# Generated by FakeRAM 2.0
VERSION 5.7 ;
BUSBITCHARS "[]" ;
PROPERTYDEFINITIONS
  MACRO width INTEGER ;
  MACRO depth INTEGER ;
  MACRO banks INTEGER ;
END PROPERTYDEFINITIONS
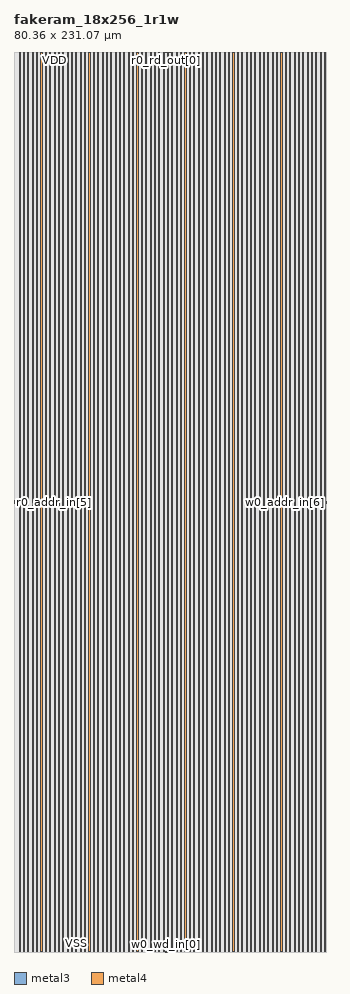
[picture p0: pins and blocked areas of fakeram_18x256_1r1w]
MACRO fakeram_18x256_1r1w
  PROPERTY width 18 ;
  PROPERTY depth 256 ;
  PROPERTY banks 1 ;
  FOREIGN fakeram_18x256_1r1w 0 0 ;
  SYMMETRY X Y R90 ;
  SIZE 80.360 BY 231.070 ;
  CLASS BLOCK ;
  PIN r0_addr_in[0]
    DIRECTION INPUT ;
    USE SIGNAL ;
    SHAPE ABUTMENT ;
    PORT
      LAYER metal3 ;
      RECT 0.000 114.800 0.070 114.870 ;
    END
  END r0_addr_in[0]
  PIN r0_addr_in[1]
    DIRECTION INPUT ;
    USE SIGNAL ;
    SHAPE ABUTMENT ;
    PORT
      LAYER metal3 ;
      RECT 0.000 114.940 0.070 115.010 ;
    END
  END r0_addr_in[1]
  PIN r0_addr_in[2]
    DIRECTION INPUT ;
    USE SIGNAL ;
    SHAPE ABUTMENT ;
    PORT
      LAYER metal3 ;
      RECT 0.000 115.080 0.070 115.150 ;
    END
  END r0_addr_in[2]
  PIN r0_addr_in[3]
    DIRECTION INPUT ;
    USE SIGNAL ;
    SHAPE ABUTMENT ;
    PORT
      LAYER metal3 ;
      RECT 0.000 115.220 0.070 115.290 ;
    END
  END r0_addr_in[3]
  PIN r0_addr_in[4]
    DIRECTION INPUT ;
    USE SIGNAL ;
    SHAPE ABUTMENT ;
    PORT
      LAYER metal3 ;
      RECT 0.000 115.360 0.070 115.430 ;
    END
  END r0_addr_in[4]
  PIN r0_addr_in[5]
    DIRECTION INPUT ;
    USE SIGNAL ;
    SHAPE ABUTMENT ;
    PORT
      LAYER metal3 ;
      RECT 0.000 115.500 0.070 115.570 ;
    END
  END r0_addr_in[5]
  PIN r0_addr_in[6]
    DIRECTION INPUT ;
    USE SIGNAL ;
    SHAPE ABUTMENT ;
    PORT
      LAYER metal3 ;
      RECT 0.000 115.640 0.070 115.710 ;
    END
  END r0_addr_in[6]
  PIN r0_addr_in[7]
    DIRECTION INPUT ;
    USE SIGNAL ;
    SHAPE ABUTMENT ;
    PORT
      LAYER metal3 ;
      RECT 0.000 115.780 0.070 115.850 ;
    END
  END r0_addr_in[7]
  PIN r0_ce_in
    DIRECTION INPUT ;
    USE SIGNAL ;
    SHAPE ABUTMENT ;
    PORT
      LAYER metal3 ;
      RECT 0.000 116.060 0.070 116.130 ;
    END
  END r0_ce_in
  PIN r0_clk
    DIRECTION INPUT ;
    USE SIGNAL ;
    SHAPE ABUTMENT ;
    PORT
      LAYER metal3 ;
      RECT 0.000 116.200 0.070 116.270 ;
    END
  END r0_clk
  PIN r0_rd_out[0]
    DIRECTION OUTPUT ;
    USE SIGNAL ;
    SHAPE ABUTMENT ;
    PORT
      LAYER metal3 ;
      RECT 38.885 231.000 38.955 231.070 ;
    END
  END r0_rd_out[0]
  PIN r0_rd_out[1]
    DIRECTION OUTPUT ;
    USE SIGNAL ;
    SHAPE ABUTMENT ;
    PORT
      LAYER metal3 ;
      RECT 39.025 231.000 39.095 231.070 ;
    END
  END r0_rd_out[1]
  PIN r0_rd_out[2]
    DIRECTION OUTPUT ;
    USE SIGNAL ;
    SHAPE ABUTMENT ;
    PORT
      LAYER metal3 ;
      RECT 39.165 231.000 39.235 231.070 ;
    END
  END r0_rd_out[2]
  PIN r0_rd_out[3]
    DIRECTION OUTPUT ;
    USE SIGNAL ;
    SHAPE ABUTMENT ;
    PORT
      LAYER metal3 ;
      RECT 39.305 231.000 39.375 231.070 ;
    END
  END r0_rd_out[3]
  PIN r0_rd_out[4]
    DIRECTION OUTPUT ;
    USE SIGNAL ;
    SHAPE ABUTMENT ;
    PORT
      LAYER metal3 ;
      RECT 39.445 231.000 39.515 231.070 ;
    END
  END r0_rd_out[4]
  PIN r0_rd_out[5]
    DIRECTION OUTPUT ;
    USE SIGNAL ;
    SHAPE ABUTMENT ;
    PORT
      LAYER metal3 ;
      RECT 39.585 231.000 39.655 231.070 ;
    END
  END r0_rd_out[5]
  PIN r0_rd_out[6]
    DIRECTION OUTPUT ;
    USE SIGNAL ;
    SHAPE ABUTMENT ;
    PORT
      LAYER metal3 ;
      RECT 39.725 231.000 39.795 231.070 ;
    END
  END r0_rd_out[6]
  PIN r0_rd_out[7]
    DIRECTION OUTPUT ;
    USE SIGNAL ;
    SHAPE ABUTMENT ;
    PORT
      LAYER metal3 ;
      RECT 39.865 231.000 39.935 231.070 ;
    END
  END r0_rd_out[7]
  PIN r0_rd_out[8]
    DIRECTION OUTPUT ;
    USE SIGNAL ;
    SHAPE ABUTMENT ;
    PORT
      LAYER metal3 ;
      RECT 40.005 231.000 40.075 231.070 ;
    END
  END r0_rd_out[8]
  PIN r0_rd_out[9]
    DIRECTION OUTPUT ;
    USE SIGNAL ;
    SHAPE ABUTMENT ;
    PORT
      LAYER metal3 ;
      RECT 40.145 231.000 40.215 231.070 ;
    END
  END r0_rd_out[9]
  PIN r0_rd_out[10]
    DIRECTION OUTPUT ;
    USE SIGNAL ;
    SHAPE ABUTMENT ;
    PORT
      LAYER metal3 ;
      RECT 40.285 231.000 40.355 231.070 ;
    END
  END r0_rd_out[10]
  PIN r0_rd_out[11]
    DIRECTION OUTPUT ;
    USE SIGNAL ;
    SHAPE ABUTMENT ;
    PORT
      LAYER metal3 ;
      RECT 40.425 231.000 40.495 231.070 ;
    END
  END r0_rd_out[11]
  PIN r0_rd_out[12]
    DIRECTION OUTPUT ;
    USE SIGNAL ;
    SHAPE ABUTMENT ;
    PORT
      LAYER metal3 ;
      RECT 40.565 231.000 40.635 231.070 ;
    END
  END r0_rd_out[12]
  PIN r0_rd_out[13]
    DIRECTION OUTPUT ;
    USE SIGNAL ;
    SHAPE ABUTMENT ;
    PORT
      LAYER metal3 ;
      RECT 40.705 231.000 40.775 231.070 ;
    END
  END r0_rd_out[13]
  PIN r0_rd_out[14]
    DIRECTION OUTPUT ;
    USE SIGNAL ;
    SHAPE ABUTMENT ;
    PORT
      LAYER metal3 ;
      RECT 40.845 231.000 40.915 231.070 ;
    END
  END r0_rd_out[14]
  PIN r0_rd_out[15]
    DIRECTION OUTPUT ;
    USE SIGNAL ;
    SHAPE ABUTMENT ;
    PORT
      LAYER metal3 ;
      RECT 40.985 231.000 41.055 231.070 ;
    END
  END r0_rd_out[15]
  PIN r0_rd_out[16]
    DIRECTION OUTPUT ;
    USE SIGNAL ;
    SHAPE ABUTMENT ;
    PORT
      LAYER metal3 ;
      RECT 41.125 231.000 41.195 231.070 ;
    END
  END r0_rd_out[16]
  PIN r0_rd_out[17]
    DIRECTION OUTPUT ;
    USE SIGNAL ;
    SHAPE ABUTMENT ;
    PORT
      LAYER metal3 ;
      RECT 41.265 231.000 41.335 231.070 ;
    END
  END r0_rd_out[17]
  PIN w0_addr_in[0]
    DIRECTION INPUT ;
    USE SIGNAL ;
    SHAPE ABUTMENT ;
    PORT
      LAYER metal3 ;
      RECT 80.290 114.660 80.360 114.730 ;
    END
  END w0_addr_in[0]
  PIN w0_addr_in[1]
    DIRECTION INPUT ;
    USE SIGNAL ;
    SHAPE ABUTMENT ;
    PORT
      LAYER metal3 ;
      RECT 80.290 114.800 80.360 114.870 ;
    END
  END w0_addr_in[1]
  PIN w0_addr_in[2]
    DIRECTION INPUT ;
    USE SIGNAL ;
    SHAPE ABUTMENT ;
    PORT
      LAYER metal3 ;
      RECT 80.290 114.940 80.360 115.010 ;
    END
  END w0_addr_in[2]
  PIN w0_addr_in[3]
    DIRECTION INPUT ;
    USE SIGNAL ;
    SHAPE ABUTMENT ;
    PORT
      LAYER metal3 ;
      RECT 80.290 115.080 80.360 115.150 ;
    END
  END w0_addr_in[3]
  PIN w0_addr_in[4]
    DIRECTION INPUT ;
    USE SIGNAL ;
    SHAPE ABUTMENT ;
    PORT
      LAYER metal3 ;
      RECT 80.290 115.220 80.360 115.290 ;
    END
  END w0_addr_in[4]
  PIN w0_addr_in[5]
    DIRECTION INPUT ;
    USE SIGNAL ;
    SHAPE ABUTMENT ;
    PORT
      LAYER metal3 ;
      RECT 80.290 115.360 80.360 115.430 ;
    END
  END w0_addr_in[5]
  PIN w0_addr_in[6]
    DIRECTION INPUT ;
    USE SIGNAL ;
    SHAPE ABUTMENT ;
    PORT
      LAYER metal3 ;
      RECT 80.290 115.500 80.360 115.570 ;
    END
  END w0_addr_in[6]
  PIN w0_addr_in[7]
    DIRECTION INPUT ;
    USE SIGNAL ;
    SHAPE ABUTMENT ;
    PORT
      LAYER metal3 ;
      RECT 80.290 115.640 80.360 115.710 ;
    END
  END w0_addr_in[7]
  PIN w0_we_in
    DIRECTION INPUT ;
    USE SIGNAL ;
    SHAPE ABUTMENT ;
    PORT
      LAYER metal3 ;
      RECT 80.290 115.920 80.360 115.990 ;
    END
  END w0_we_in
  PIN w0_ce_in
    DIRECTION INPUT ;
    USE SIGNAL ;
    SHAPE ABUTMENT ;
    PORT
      LAYER metal3 ;
      RECT 80.290 116.060 80.360 116.130 ;
    END
  END w0_ce_in
  PIN w0_clk
    DIRECTION INPUT ;
    USE SIGNAL ;
    SHAPE ABUTMENT ;
    PORT
      LAYER metal3 ;
      RECT 80.290 116.200 80.360 116.270 ;
    END
  END w0_clk
  PIN w0_wd_in[0]
    DIRECTION INPUT ;
    USE SIGNAL ;
    SHAPE ABUTMENT ;
    PORT
      LAYER metal3 ;
      RECT 38.885 0.000 38.955 0.070 ;
    END
  END w0_wd_in[0]
  PIN w0_wd_in[1]
    DIRECTION INPUT ;
    USE SIGNAL ;
    SHAPE ABUTMENT ;
    PORT
      LAYER metal3 ;
      RECT 39.025 0.000 39.095 0.070 ;
    END
  END w0_wd_in[1]
  PIN w0_wd_in[2]
    DIRECTION INPUT ;
    USE SIGNAL ;
    SHAPE ABUTMENT ;
    PORT
      LAYER metal3 ;
      RECT 39.165 0.000 39.235 0.070 ;
    END
  END w0_wd_in[2]
  PIN w0_wd_in[3]
    DIRECTION INPUT ;
    USE SIGNAL ;
    SHAPE ABUTMENT ;
    PORT
      LAYER metal3 ;
      RECT 39.305 0.000 39.375 0.070 ;
    END
  END w0_wd_in[3]
  PIN w0_wd_in[4]
    DIRECTION INPUT ;
    USE SIGNAL ;
    SHAPE ABUTMENT ;
    PORT
      LAYER metal3 ;
      RECT 39.445 0.000 39.515 0.070 ;
    END
  END w0_wd_in[4]
  PIN w0_wd_in[5]
    DIRECTION INPUT ;
    USE SIGNAL ;
    SHAPE ABUTMENT ;
    PORT
      LAYER metal3 ;
      RECT 39.585 0.000 39.655 0.070 ;
    END
  END w0_wd_in[5]
  PIN w0_wd_in[6]
    DIRECTION INPUT ;
    USE SIGNAL ;
    SHAPE ABUTMENT ;
    PORT
      LAYER metal3 ;
      RECT 39.725 0.000 39.795 0.070 ;
    END
  END w0_wd_in[6]
  PIN w0_wd_in[7]
    DIRECTION INPUT ;
    USE SIGNAL ;
    SHAPE ABUTMENT ;
    PORT
      LAYER metal3 ;
      RECT 39.865 0.000 39.935 0.070 ;
    END
  END w0_wd_in[7]
  PIN w0_wd_in[8]
    DIRECTION INPUT ;
    USE SIGNAL ;
    SHAPE ABUTMENT ;
    PORT
      LAYER metal3 ;
      RECT 40.005 0.000 40.075 0.070 ;
    END
  END w0_wd_in[8]
  PIN w0_wd_in[9]
    DIRECTION INPUT ;
    USE SIGNAL ;
    SHAPE ABUTMENT ;
    PORT
      LAYER metal3 ;
      RECT 40.145 0.000 40.215 0.070 ;
    END
  END w0_wd_in[9]
  PIN w0_wd_in[10]
    DIRECTION INPUT ;
    USE SIGNAL ;
    SHAPE ABUTMENT ;
    PORT
      LAYER metal3 ;
      RECT 40.285 0.000 40.355 0.070 ;
    END
  END w0_wd_in[10]
  PIN w0_wd_in[11]
    DIRECTION INPUT ;
    USE SIGNAL ;
    SHAPE ABUTMENT ;
    PORT
      LAYER metal3 ;
      RECT 40.425 0.000 40.495 0.070 ;
    END
  END w0_wd_in[11]
  PIN w0_wd_in[12]
    DIRECTION INPUT ;
    USE SIGNAL ;
    SHAPE ABUTMENT ;
    PORT
      LAYER metal3 ;
      RECT 40.565 0.000 40.635 0.070 ;
    END
  END w0_wd_in[12]
  PIN w0_wd_in[13]
    DIRECTION INPUT ;
    USE SIGNAL ;
    SHAPE ABUTMENT ;
    PORT
      LAYER metal3 ;
      RECT 40.705 0.000 40.775 0.070 ;
    END
  END w0_wd_in[13]
  PIN w0_wd_in[14]
    DIRECTION INPUT ;
    USE SIGNAL ;
    SHAPE ABUTMENT ;
    PORT
      LAYER metal3 ;
      RECT 40.845 0.000 40.915 0.070 ;
    END
  END w0_wd_in[14]
  PIN w0_wd_in[15]
    DIRECTION INPUT ;
    USE SIGNAL ;
    SHAPE ABUTMENT ;
    PORT
      LAYER metal3 ;
      RECT 40.985 0.000 41.055 0.070 ;
    END
  END w0_wd_in[15]
  PIN w0_wd_in[16]
    DIRECTION INPUT ;
    USE SIGNAL ;
    SHAPE ABUTMENT ;
    PORT
      LAYER metal3 ;
      RECT 41.125 0.000 41.195 0.070 ;
    END
  END w0_wd_in[16]
  PIN w0_wd_in[17]
    DIRECTION INPUT ;
    USE SIGNAL ;
    SHAPE ABUTMENT ;
    PORT
      LAYER metal3 ;
      RECT 41.265 0.000 41.335 0.070 ;
    END
  END w0_wd_in[17]
  PIN VSS
    DIRECTION INOUT ;
    USE GROUND ;
    PORT
      LAYER metal4 ;
      RECT 2.450 0.140 2.730 230.930 ;
      RECT 4.690 0.140 4.970 230.930 ;
      RECT 6.930 0.140 7.210 230.930 ;
      RECT 9.170 0.140 9.450 230.930 ;
      RECT 11.410 0.140 11.690 230.930 ;
      RECT 13.650 0.140 13.930 230.930 ;
      RECT 15.890 0.140 16.170 230.930 ;
      RECT 18.130 0.140 18.410 230.930 ;
      RECT 20.370 0.140 20.650 230.930 ;
      RECT 22.610 0.140 22.890 230.930 ;
      RECT 24.850 0.140 25.130 230.930 ;
      RECT 27.090 0.140 27.370 230.930 ;
      RECT 29.330 0.140 29.610 230.930 ;
      RECT 31.570 0.140 31.850 230.930 ;
      RECT 33.810 0.140 34.090 230.930 ;
      RECT 36.050 0.140 36.330 230.930 ;
      RECT 38.290 0.140 38.570 230.930 ;
      RECT 40.530 0.140 40.810 230.930 ;
      RECT 42.770 0.140 43.050 230.930 ;
      RECT 45.010 0.140 45.290 230.930 ;
      RECT 47.250 0.140 47.530 230.930 ;
      RECT 49.490 0.140 49.770 230.930 ;
      RECT 51.730 0.140 52.010 230.930 ;
      RECT 53.970 0.140 54.250 230.930 ;
      RECT 56.210 0.140 56.490 230.930 ;
      RECT 58.450 0.140 58.730 230.930 ;
      RECT 60.690 0.140 60.970 230.930 ;
      RECT 62.930 0.140 63.210 230.930 ;
      RECT 65.170 0.140 65.450 230.930 ;
      RECT 67.410 0.140 67.690 230.930 ;
      RECT 69.650 0.140 69.930 230.930 ;
      RECT 71.890 0.140 72.170 230.930 ;
      RECT 74.130 0.140 74.410 230.930 ;
      RECT 76.370 0.140 76.650 230.930 ;
      RECT 78.610 0.140 78.890 230.930 ;
    END
  END VSS
  PIN VDD
    DIRECTION INOUT ;
    USE POWER ;
    PORT
      LAYER metal4 ;
      RECT 1.330 0.140 1.610 230.930 ;
      RECT 3.570 0.140 3.850 230.930 ;
      RECT 5.810 0.140 6.090 230.930 ;
      RECT 8.050 0.140 8.330 230.930 ;
      RECT 10.290 0.140 10.570 230.930 ;
      RECT 12.530 0.140 12.810 230.930 ;
      RECT 14.770 0.140 15.050 230.930 ;
      RECT 17.010 0.140 17.290 230.930 ;
      RECT 19.250 0.140 19.530 230.930 ;
      RECT 21.490 0.140 21.770 230.930 ;
      RECT 23.730 0.140 24.010 230.930 ;
      RECT 25.970 0.140 26.250 230.930 ;
      RECT 28.210 0.140 28.490 230.930 ;
      RECT 30.450 0.140 30.730 230.930 ;
      RECT 32.690 0.140 32.970 230.930 ;
      RECT 34.930 0.140 35.210 230.930 ;
      RECT 37.170 0.140 37.450 230.930 ;
      RECT 39.410 0.140 39.690 230.930 ;
      RECT 41.650 0.140 41.930 230.930 ;
      RECT 43.890 0.140 44.170 230.930 ;
      RECT 46.130 0.140 46.410 230.930 ;
      RECT 48.370 0.140 48.650 230.930 ;
      RECT 50.610 0.140 50.890 230.930 ;
      RECT 52.850 0.140 53.130 230.930 ;
      RECT 55.090 0.140 55.370 230.930 ;
      RECT 57.330 0.140 57.610 230.930 ;
      RECT 59.570 0.140 59.850 230.930 ;
      RECT 61.810 0.140 62.090 230.930 ;
      RECT 64.050 0.140 64.330 230.930 ;
      RECT 66.290 0.140 66.570 230.930 ;
      RECT 68.530 0.140 68.810 230.930 ;
      RECT 70.770 0.140 71.050 230.930 ;
      RECT 73.010 0.140 73.290 230.930 ;
      RECT 75.250 0.140 75.530 230.930 ;
      RECT 77.490 0.140 77.770 230.930 ;
      RECT 79.730 0.140 80.010 230.930 ;
    END
  END VDD
  OBS
    LAYER metal1 ;
    RECT 0 0 80.360 231.070 ;
    LAYER metal2 ;
    RECT 0 0 80.360 231.070 ;
    LAYER metal3 ;
    RECT 0 0 80.360 231.070 ;
    LAYER metal4 ;
    RECT 0 0 80.360 231.070 ;
    LAYER OVERLAP ;
    RECT 0 0 80.360 231.070 ;
  END
END fakeram_18x256_1r1w

END LIBRARY
